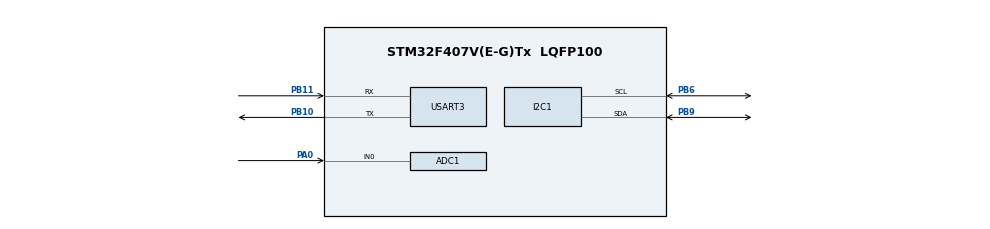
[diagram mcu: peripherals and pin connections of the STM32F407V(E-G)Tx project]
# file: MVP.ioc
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ADC1.Channel-0\#ChannelRegularConversion=ADC_CHANNEL_0
ADC1.NbrOfConversionFlag=1
ADC1.Rank-0\#ChannelRegularConversion=1
ADC1.SamplingTime-0\#ChannelRegularConversion=ADC_SAMPLETIME_3CYCLES
ADC1.master=1
Dma.Request0=USART3_RX
Dma.Request1=USART3_TX
Dma.USART3_RX.0.Direction=DMA_PERIPH_TO_MEMORY
Dma.USART3_RX.0.FIFOMode=DMA_FIFOMODE_DISABLE
Dma.USART3_RX.0.Instance=DMA1_Stream1
Dma.USART3_RX.0.MemDataAlignment=DMA_MDATAALIGN_BYTE
Dma.USART3_RX.0.MemInc=DMA_MINC_ENABLE
Dma.USART3_RX.0.Mode=DMA_NORMAL
Dma.USART3_RX.0.PeriphDataAlignment=DMA_PDATAALIGN_BYTE
Dma.USART3_RX.0.PeriphInc=DMA_PINC_DISABLE
Dma.USART3_RX.0.Priority=DMA_PRIORITY_LOW
Dma.USART3_TX.1.Direction=DMA_MEMORY_TO_PERIPH
Dma.USART3_TX.1.FIFOMode=DMA_FIFOMODE_DISABLE
Dma.USART3_TX.1.Instance=DMA1_Stream3
Dma.USART3_TX.1.MemDataAlignment=DMA_MDATAALIGN_BYTE
Dma.USART3_TX.1.MemInc=DMA_MINC_ENABLE
Dma.USART3_TX.1.Mode=DMA_NORMAL
Dma.USART3_TX.1.PeriphDataAlignment=DMA_PDATAALIGN_BYTE
Dma.USART3_TX.1.PeriphInc=DMA_PINC_DISABLE
Dma.USART3_TX.1.Priority=DMA_PRIORITY_LOW
Mcu.Family=STM32F4
Mcu.Name=STM32F407V(E-G)Tx
Mcu.Package=LQFP100
NVIC.DMA1_Stream1_IRQn=true\:0\:0\:false\:false\:true\:false\:true\:true
NVIC.DMA1_Stream3_IRQn=true\:0\:0\:false\:false\:true\:false\:true\:true
NVIC.PriorityGroup=NVIC_PRIORITYGROUP_0
NVIC.USART3_IRQn=true\:0\:0\:false\:false\:true\:true\:true\:true
PA0-WKUP.Signal=ADCx_IN0
PB10.Mode=Asynchronous
PB10.Signal=USART3_TX
PB11.Mode=Asynchronous
PB11.Signal=USART3_RX
PB6.Mode=I2C
PB6.Signal=I2C1_SCL
PB9.Mode=I2C
PB9.Signal=I2C1_SDA
PH0-OSC_IN.Mode=HSE-External-Oscillator
PH0-OSC_IN.Signal=RCC_OSC_IN
PH1-OSC_OUT.Mode=HSE-External-Oscillator
PH1-OSC_OUT.Signal=RCC_OSC_OUT
ProjectManager.HeapSize=0x200
ProjectManager.StackSize=0x400
ProjectManager.TargetToolchain=STM32CubeIDE
RCC.48MHZClocksFreq_Value=48000000
RCC.AHBFreq_Value=168000000
RCC.APB1CLKDivider=RCC_HCLK_DIV4
RCC.APB1Freq_Value=42000000
RCC.APB1TimFreq_Value=84000000
RCC.APB2CLKDivider=RCC_HCLK_DIV2
RCC.APB2Freq_Value=84000000
RCC.APB2TimFreq_Value=168000000
RCC.CortexFreq_Value=168000000
RCC.HCLKFreq_Value=168000000
RCC.HSE_VALUE=8000000
RCC.HSI_VALUE=16000000
RCC.LSE_VALUE=32768
RCC.PLLM=8
RCC.PLLN=336
RCC.PLLQ=7
RCC.PLLSourceVirtual=RCC_PLLSOURCE_HSE
RCC.SYSCLKFreq_VALUE=168000000
RCC.SYSCLKSource=RCC_SYSCLKSOURCE_PLLCLK
RCC.VCOOutputFreq_Value=336000000
SH.ADCx_IN0.0=ADC1_IN0,IN0
USART3.VirtualMode=VM_ASYNC
board=STM32F407G-DISC1

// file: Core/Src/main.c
/* USER CODE BEGIN Header */
/**
 ******************************************************************************
 * @file           : main.c
 * @brief          : Main program body
 ******************************************************************************
 * @attention
 *
 * Copyright (c) 2024 STMicroelectronics.
 * All rights reserved.
 *
 * This software is licensed under terms that can be found in the LICENSE file
 * in the root directory of this software component.
 * If no LICENSE file comes with this software, it is provided AS-IS.
 *
 ******************************************************************************
 */
/* USER CODE END Header */
#include "main.h"

/* USER CODE BEGIN Includes */
#include "NvM.h"
#include "Dem.h"
#include "Events.h"
#include "check_voltage.h"
#include <stdio.h>
#include "DLTuc.h"
/* USER CODE END Includes */

ADC_HandleTypeDef hadc1;

I2C_HandleTypeDef hi2c1;

UART_HandleTypeDef huart3;
DMA_HandleTypeDef hdma_usart3_tx;
DMA_HandleTypeDef hdma_usart3_rx;

void SystemClock_Config(void);
static void MX_GPIO_Init(void);
static void MX_DMA_Init(void);
static void MX_I2C1_Init(void);
static void MX_ADC1_Init(void);
static void MX_USART3_UART_Init(void);

/* USER CODE BEGIN 0 */
void HAL_UARTEx_RxEventCallback(UART_HandleTypeDef *huart, uint16_t Size)
{
	  DLTuc_RawDataReceiveDone(Size);
}

void HAL_UART_TxCpltCallback(UART_HandleTypeDef *huart)
{
	  DLTuc_MessageTransmitDone();
}

void LLSerialTrDataFunctionC(uint8_t *DltLogData, uint8_t Size)
{
	HAL_UART_Transmit_DMA(&huart3, DltLogData, Size);
}

void LLSerialRecDataFunctionC(uint8_t *DltLogData, uint16_t Size)
{
	HAL_UARTEx_ReceiveToIdle_DMA(&huart3, DltLogData, Size);
}

void DltInjectDataRcvd(uint32_t AppId, uint32_t ConId,uint32_t ServId,uint8_t *Data, uint16_t Size)
{
	LOG("RecInjectionData: %s, ServId: %d Size: %d", Data,ServId,Size)
	if(strstr(Data, "Read DTC") != NULL)
	{
		uint8_t overvoltage_status = 0u;
		uint8_t undervoltage_status = 0u;

		Dem_GetStatusOfDTC(OVER_VOLTAGE_ID, &overvoltage_status);
		Dem_GetStatusOfDTC(UNDER_VOLTAGE_ID, &undervoltage_status);
		LOGL(DL_INFO, "OVERVOLTAGE STATUS: %x", overvoltage_status);
		LOGL(DL_INFO, "UNDERVOLTAGE STATUS: %x", undervoltage_status);
	}
}
/* USER CODE END 0 */

int main(void)
{
  /* USER CODE BEGIN 1 */

	uint32_t vol = 0;

  /* USER CODE END 1 */

  /* MCU Configuration--------------------------------------------------------*/

  /* Reset of all peripherals, Initializes the Flash interface and the Systick. */
  HAL_Init();

  /* Configure the system clock */
  SystemClock_Config();

  /* Initialize all configured peripherals */
  MX_GPIO_Init();
  MX_DMA_Init();
  MX_I2C1_Init();
  MX_ADC1_Init();
  MX_USART3_UART_Init();
  /* USER CODE BEGIN 2 */

	/*Register Low Level Transmit/Receive functions for DLTuc Library*/
	DLTuc_RegisterTransmitSerialDataFunction(LLSerialTrDataFunctionC);
	DLTuc_RegisterReceiveSerialDataFunction(LLSerialRecDataFunctionC);

	DLTuc_RegisterGetTimeStampMsCallback(HAL_GetTick); 	/*Register GetSysTime function*/
	/*The function "GetSysTime" must return the time in ms*/

	DLTuc_RegisterInjectionDataReceivedCb(DltInjectDataRcvd);

	/*Now ucDLTlib is ready to work!*/
	LOGL(DL_INFO, "DLT TESTS START!!!");

  HAL_ADC_Start(&hadc1);
  HAL_ADC_PollForConversion(&hadc1, 20);
  vol = HAL_ADC_GetValue(&hadc1);

  Check_Voltage(vol);
  HAL_Delay(5);
  uint8_t overvoltageStatus[4] = {0};
  uint8_t undervoltageStatus[4] = {0};
  Dem_GetStatusOfDTC(OVER_VOLTAGE_ID, overvoltageStatus);
  Dem_GetStatusOfDTC(UNDER_VOLTAGE_ID, undervoltageStatus);

  /* USER CODE END 2 */

  /* Infinite loop */
  while (1)
  {

  }
}

void SystemClock_Config(void)
{
  RCC_OscInitTypeDef RCC_OscInitStruct = {0};
  RCC_ClkInitTypeDef RCC_ClkInitStruct = {0};

  /** Configure the main internal regulator output voltage
  */
  __HAL_RCC_PWR_CLK_ENABLE();
  __HAL_PWR_VOLTAGESCALING_CONFIG(PWR_REGULATOR_VOLTAGE_SCALE1);

  /** Initializes the RCC Oscillators according to the specified parameters
  * in the RCC_OscInitTypeDef structure.
  */
  RCC_OscInitStruct.OscillatorType = RCC_OSCILLATORTYPE_HSI;
  RCC_OscInitStruct.HSIState = RCC_HSI_ON;
  RCC_OscInitStruct.HSICalibrationValue = RCC_HSICALIBRATION_DEFAULT;
  RCC_OscInitStruct.PLL.PLLState = RCC_PLL_ON;
  RCC_OscInitStruct.PLL.PLLSource = RCC_PLLSOURCE_HSI;
  RCC_OscInitStruct.PLL.PLLM = 8;
  RCC_OscInitStruct.PLL.PLLN = 50;
  RCC_OscInitStruct.PLL.PLLP = RCC_PLLP_DIV2;
  RCC_OscInitStruct.PLL.PLLQ = 7;
  if (HAL_RCC_OscConfig(&RCC_OscInitStruct) != HAL_OK)
  {
    Error_Handler();
  }

  /** Initializes the CPU, AHB and APB buses clocks
  */
  RCC_ClkInitStruct.ClockType = RCC_CLOCKTYPE_HCLK|RCC_CLOCKTYPE_SYSCLK
                              |RCC_CLOCKTYPE_PCLK1|RCC_CLOCKTYPE_PCLK2;
  RCC_ClkInitStruct.SYSCLKSource = RCC_SYSCLKSOURCE_PLLCLK;
  RCC_ClkInitStruct.AHBCLKDivider = RCC_SYSCLK_DIV1;
  RCC_ClkInitStruct.APB1CLKDivider = RCC_HCLK_DIV4;
  RCC_ClkInitStruct.APB2CLKDivider = RCC_HCLK_DIV2;

  if (HAL_RCC_ClockConfig(&RCC_ClkInitStruct, FLASH_LATENCY_1) != HAL_OK)
  {
    Error_Handler();
  }
}

static void MX_ADC1_Init(void)
{

  ADC_ChannelConfTypeDef sConfig = {0};

  /** Configure the global features of the ADC (Clock, Resolution, Data Alignment and number of conversion)
  */
  hadc1.Instance = ADC1;
  hadc1.Init.ClockPrescaler = ADC_CLOCK_SYNC_PCLK_DIV2;
  hadc1.Init.Resolution = ADC_RESOLUTION_12B;
  hadc1.Init.ScanConvMode = DISABLE;
  hadc1.Init.ContinuousConvMode = DISABLE;
  hadc1.Init.DiscontinuousConvMode = DISABLE;
  hadc1.Init.ExternalTrigConvEdge = ADC_EXTERNALTRIGCONVEDGE_NONE;
  hadc1.Init.ExternalTrigConv = ADC_SOFTWARE_START;
  hadc1.Init.DataAlign = ADC_DATAALIGN_RIGHT;
  hadc1.Init.NbrOfConversion = 1;
  hadc1.Init.DMAContinuousRequests = DISABLE;
  hadc1.Init.EOCSelection = ADC_EOC_SINGLE_CONV;
  if (HAL_ADC_Init(&hadc1) != HAL_OK)
  {
    Error_Handler();
  }

  /** Configure for the selected ADC regular channel its corresponding rank in the sequencer and its sample time.
  */
  sConfig.Channel = ADC_CHANNEL_0;
  sConfig.Rank = 1;
  sConfig.SamplingTime = ADC_SAMPLETIME_3CYCLES;
  if (HAL_ADC_ConfigChannel(&hadc1, &sConfig) != HAL_OK)
  {
    Error_Handler();
  }

}

static void MX_I2C1_Init(void)
{

  hi2c1.Instance = I2C1;
  hi2c1.Init.ClockSpeed = 100000;
  hi2c1.Init.DutyCycle = I2C_DUTYCYCLE_2;
  hi2c1.Init.OwnAddress1 = 0;
  hi2c1.Init.AddressingMode = I2C_ADDRESSINGMODE_7BIT;
  hi2c1.Init.DualAddressMode = I2C_DUALADDRESS_DISABLE;
  hi2c1.Init.OwnAddress2 = 0;
  hi2c1.Init.GeneralCallMode = I2C_GENERALCALL_DISABLE;
  hi2c1.Init.NoStretchMode = I2C_NOSTRETCH_DISABLE;
  if (HAL_I2C_Init(&hi2c1) != HAL_OK)
  {
    Error_Handler();
  }

}

static void MX_USART3_UART_Init(void)
{

  huart3.Instance = USART3;
  huart3.Init.BaudRate = 115200;
  huart3.Init.WordLength = UART_WORDLENGTH_8B;
  huart3.Init.StopBits = UART_STOPBITS_1;
  huart3.Init.Parity = UART_PARITY_NONE;
  huart3.Init.Mode = UART_MODE_TX_RX;
  huart3.Init.HwFlowCtl = UART_HWCONTROL_NONE;
  huart3.Init.OverSampling = UART_OVERSAMPLING_16;
  if (HAL_UART_Init(&huart3) != HAL_OK)
  {
    Error_Handler();
  }

}

static void MX_DMA_Init(void)
{

  /* DMA controller clock enable */
  __HAL_RCC_DMA1_CLK_ENABLE();

  /* DMA interrupt init */
  /* DMA1_Stream1_IRQn interrupt configuration */
  HAL_NVIC_SetPriority(DMA1_Stream1_IRQn, 0, 0);
  HAL_NVIC_EnableIRQ(DMA1_Stream1_IRQn);
  /* DMA1_Stream3_IRQn interrupt configuration */
  HAL_NVIC_SetPriority(DMA1_Stream3_IRQn, 0, 0);
  HAL_NVIC_EnableIRQ(DMA1_Stream3_IRQn);

}

static void MX_GPIO_Init(void)
{

  /* GPIO Ports Clock Enable */
  __HAL_RCC_GPIOH_CLK_ENABLE();
  __HAL_RCC_GPIOA_CLK_ENABLE();
  __HAL_RCC_GPIOB_CLK_ENABLE();

}

void Error_Handler(void)
{
  __disable_irq();
  while (1)
  {
  }
}
